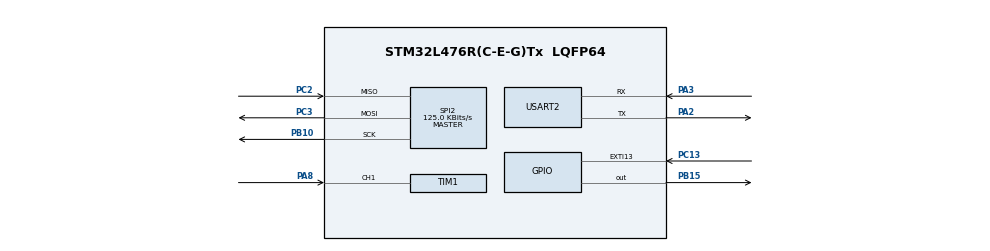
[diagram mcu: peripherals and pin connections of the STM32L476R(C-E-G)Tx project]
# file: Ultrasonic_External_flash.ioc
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Mcu.Family=STM32L4
Mcu.Name=STM32L476R(C-E-G)Tx
Mcu.Package=LQFP64
NVIC.EXTI15_10_IRQn=true\:0\:0\:false\:false\:true\:true\:true\:true
NVIC.PriorityGroup=NVIC_PRIORITYGROUP_4
NVIC.TIM1_CC_IRQn=true\:0\:0\:false\:false\:true\:true\:true\:true
PA2.Mode=Asynchronous
PA2.Signal=USART2_TX
PA3.Mode=Asynchronous
PA3.Signal=USART2_RX
PA8.Signal=S_TIM1_CH1
PB10.Mode=Full_Duplex_Master
PB10.Signal=SPI2_SCK
PB15.Signal=GPIO_Output
PC13.Signal=GPXTI13
PC2.Mode=Full_Duplex_Master
PC2.Signal=SPI2_MISO
PC3.Mode=Full_Duplex_Master
PC3.Signal=SPI2_MOSI
PH0-OSC_IN\ (PH0).Mode=HSE-External-Oscillator
PH0-OSC_IN\ (PH0).Signal=RCC_OSC_IN
PH1-OSC_OUT\ (PH1).Mode=HSE-External-Oscillator
PH1-OSC_OUT\ (PH1).Signal=RCC_OSC_OUT
ProjectManager.HeapSize=0x200
ProjectManager.StackSize=0x400
ProjectManager.TargetToolchain=STM32CubeIDE
RCC.HSE_VALUE=8000000
RCC.HSI_VALUE=16000000
RCC.LSE_VALUE=32768
RCC.MSI_VALUE=4000000
RCC.VCOOutputFreq_Value=32000000
SH.S_TIM1_CH1.0=TIM1_CH1,Input_Capture1_from_TI1
SPI2.BaudRatePrescaler=SPI_BAUDRATEPRESCALER_32
SPI2.CalculateBaudRate=125.0 KBits/s
SPI2.DataSize=SPI_DATASIZE_8BIT
SPI2.Direction=SPI_DIRECTION_2LINES
SPI2.Mode=SPI_MODE_MASTER
SPI2.VirtualType=VM_MASTER
TIM1.Channel-Input_Capture1_from_TI1=TIM_CHANNEL_1
TIM1.Prescaler=80-1
USART2.VirtualMode-Asynchronous=VM_ASYNC
board=custom

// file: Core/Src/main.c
/* USER CODE BEGIN Header */
/**
  ******************************************************************************
  * @file           : main.c
  * @brief          : Main program body
  ******************************************************************************
  * @attention
  *
  * Copyright (c) 2025 STMicroelectronics.
  * All rights reserved.
  *
  ******************************************************************************
  */
/* USER CODE END Header */
#include "main.h"

/* USER CODE BEGIN Includes */
#include "w25qxx.h"
#include <stdio.h>
#include <string.h>
/* USER CODE END Includes */

void SystemClock_Config(void);
static void MX_GPIO_Init(void);
static void MX_USART2_UART_Init(void);
static void MX_TIM1_Init(void);
static void MX_SPI2_Init(void);

SPI_HandleTypeDef hspi2;
TIM_HandleTypeDef htim1;
UART_HandleTypeDef huart2;

/* USER CODE BEGIN PV */
uint32_t IC_Val1 = 0;
uint32_t IC_Val2 = 0;
uint32_t Difference = 0;
uint8_t Is_First_Captured = 0;
uint16_t Distance = 0, object_present = 0;
uint8_t flash_buffer[256];
uint32_t ID;
/* USER CODE END PV */

/* USER CODE BEGIN PD */
#define TRIG_PIN   GPIO_PIN_15
#define TRIG_PORT  GPIOB
/* USER CODE END PD */

/* USER CODE BEGIN 0 */

void HAL_TIM_IC_CaptureCallback(TIM_HandleTypeDef *htim)
{
    if (htim->Channel == HAL_TIM_ACTIVE_CHANNEL_1)
    {
        if (Is_First_Captured == 0)
        {
            IC_Val1 = HAL_TIM_ReadCapturedValue(htim, TIM_CHANNEL_1);
            Is_First_Captured = 1;
            __HAL_TIM_SET_CAPTUREPOLARITY(htim, TIM_CHANNEL_1,
                                          TIM_INPUTCHANNELPOLARITY_FALLING);
        }
        else
        {
            IC_Val2 = HAL_TIM_ReadCapturedValue(htim, TIM_CHANNEL_1);
            __HAL_TIM_SET_COUNTER(htim, 0);

            if (IC_Val2 > IC_Val1)
                Difference = IC_Val2 - IC_Val1;
            else
                Difference = (0xffff - IC_Val1) + IC_Val2;

            Distance = (uint16_t)(Difference * 0.034f / 2.0f);

            Is_First_Captured = 0;
            __HAL_TIM_SET_CAPTUREPOLARITY(htim, TIM_CHANNEL_1,
                                          TIM_INPUTCHANNELPOLARITY_RISING);
            __HAL_TIM_DISABLE_IT(&htim1, TIM_IT_CC1);
        }
    }
}

uint16_t HCSR04_Read(void)
{
    uint32_t timeout = HAL_GetTick();

    HAL_GPIO_WritePin(TRIG_PORT, TRIG_PIN, GPIO_PIN_SET);
    for (volatile int i = 0; i < 800; i++);
    HAL_GPIO_WritePin(TRIG_PORT, TRIG_PIN, GPIO_PIN_RESET);

    __HAL_TIM_ENABLE_IT(&htim1, TIM_IT_CC1);

    while (Is_First_Captured || Distance == 0)
    {
        if ((HAL_GetTick() - timeout) > 30)
        {
            Distance = 0;
            break;
        }
    }
    return Distance;
}

/* Button EXTI callback: reads flash pages and prints via UART */
void HAL_GPIO_EXTI_Callback(uint16_t GPIO_Pin)
{
    if (GPIO_Pin == B1_Pin)
    {
        HAL_UART_Transmit(&huart2, (uint8_t *)"\r\n--- FLASH LOG DUMP ---\r\n", 27, 200);

        for (uint8_t i = 0; i < 10; i++)
        {
            memset(flash_buffer, 0, sizeof(flash_buffer));
            /* read page i, offset 0, up to 256 bytes */
            W25q_Read(i, 0, 256, flash_buffer);
            flash_buffer[255] = '\0';   // force null termination

            // find first 0xFF or 0x00 to stop
            for(int k = 0; k < 256; k++)
            {
                if(flash_buffer[k] == 0xFF || flash_buffer[k] == 0x00)
                {
                    flash_buffer[k] = '\0';
                    break;
                }
            }

            HAL_UART_Transmit(&huart2, flash_buffer, strlen((char*)flash_buffer), 200);

        }

        HAL_UART_Transmit(&huart2, (uint8_t *)"--- END ---\r\n", 13, 100);
    }
}

/* USER CODE END 0 */

int main(void)
{
  HAL_Init();
  SystemClock_Config();

  MX_GPIO_Init();
  MX_USART2_UART_Init();
  MX_TIM1_Init();
  MX_SPI2_Init();

  HAL_TIM_IC_Start_IT(&htim1, TIM_CHANNEL_1);

  /* Initialize / reset flash and read ID */
  W25Q_RESET();
  ID = W25_ReadID();

  uint8_t cnt = 0;
  uint16_t last_d = 0;

  while (1)
  {
      Distance = HCSR04_Read();

      if (Distance > 0 && Distance < 150)
      {
          if (object_present == 0)
          {
              char msg[80];
              int len = snprintf(msg, sizeof(msg), "Object entered: %u cm\r\n", Distance);
              if (len > 0)
              {
                  HAL_UART_Transmit(&huart2, (uint8_t *)msg, (uint16_t)len, 100);
                  flash_write(cnt, 0, (uint32_t)len, (uint8_t *)msg); // write then increment
                  cnt++;
              }

              last_d = Distance;
              object_present = 1;
          }
      }
      else
      {
          if (object_present == 1)
          {
              char msg[80];
              int len = snprintf(msg, sizeof(msg), "Object removed: %u cm\r\n", last_d);
              if (len > 0)
              {
                  HAL_UART_Transmit(&huart2, (uint8_t *)msg, (uint16_t)len, 100);
                  flash_write(cnt, 0, (uint32_t)len, (uint8_t *)msg); // write then increment
                  cnt++;
              }

              object_present = 0;
          }
      }

      if (cnt >= 10) cnt = 0; /* simple circular 10-page buffer */

      HAL_Delay(200);
  }
}

/* ---------------- System and Peripheral Initialization -------------------- */

void SystemClock_Config(void)
{
  RCC_OscInitTypeDef RCC_OscInitStruct = {0};
  RCC_ClkInitTypeDef RCC_ClkInitStruct = {0};

  if (HAL_PWREx_ControlVoltageScaling(PWR_REGULATOR_VOLTAGE_SCALE1) != HAL_OK)
  {
    Error_Handler();
  }

  RCC_OscInitStruct.OscillatorType = RCC_OSCILLATORTYPE_HSI;
  RCC_OscInitStruct.HSIState = RCC_HSI_ON;
  RCC_OscInitStruct.HSICalibrationValue = RCC_HSICALIBRATION_DEFAULT;
  RCC_OscInitStruct.PLL.PLLState = RCC_PLL_ON;
  RCC_OscInitStruct.PLL.PLLSource = RCC_PLLSOURCE_HSI;
  RCC_OscInitStruct.PLL.PLLM = 1;
  RCC_OscInitStruct.PLL.PLLN = 10;
  RCC_OscInitStruct.PLL.PLLP = RCC_PLLP_DIV7;
  RCC_OscInitStruct.PLL.PLLQ = RCC_PLLQ_DIV2;
  RCC_OscInitStruct.PLL.PLLR = RCC_PLLR_DIV2;

  if (HAL_RCC_OscConfig(&RCC_OscInitStruct) != HAL_OK) Error_Handler();

  RCC_ClkInitStruct.ClockType = RCC_CLOCKTYPE_HCLK|RCC_CLOCKTYPE_SYSCLK
                              |RCC_CLOCKTYPE_PCLK1|RCC_CLOCKTYPE_PCLK2;
  RCC_ClkInitStruct.SYSCLKSource = RCC_SYSCLKSOURCE_PLLCLK;
  RCC_ClkInitStruct.AHBCLKDivider = RCC_SYSCLK_DIV1;
  RCC_ClkInitStruct.APB1CLKDivider = RCC_HCLK_DIV1;
  RCC_ClkInitStruct.APB2CLKDivider = RCC_HCLK_DIV1;

  if (HAL_RCC_ClockConfig(&RCC_ClkInitStruct, FLASH_LATENCY_4) != HAL_OK) Error_Handler();
}

static void MX_SPI2_Init(void)
{
  /* SPI2 init - master mode */
  hspi2.Instance = SPI2;
  hspi2.Init.Mode = SPI_MODE_MASTER;
  hspi2.Init.Direction = SPI_DIRECTION_2LINES;
  hspi2.Init.DataSize = SPI_DATASIZE_8BIT;
  hspi2.Init.CLKPolarity = SPI_POLARITY_LOW;
  hspi2.Init.CLKPhase = SPI_PHASE_1EDGE;
  hspi2.Init.NSS = SPI_NSS_SOFT;
  hspi2.Init.BaudRatePrescaler = SPI_BAUDRATEPRESCALER_32;
  hspi2.Init.FirstBit = SPI_FIRSTBIT_MSB;
  hspi2.Init.TIMode = SPI_TIMODE_DISABLE;
  hspi2.Init.CRCCalculation = SPI_CRCCALCULATION_DISABLE;

  if (HAL_SPI_Init(&hspi2) != HAL_OK) Error_Handler();
}

static void MX_TIM1_Init(void)
{
  TIM_MasterConfigTypeDef sMasterConfig = {0};
  TIM_IC_InitTypeDef sConfigIC = {0};

  htim1.Instance = TIM1;
  htim1.Init.Prescaler = 80 - 1;
  htim1.Init.CounterMode = TIM_COUNTERMODE_UP;
  htim1.Init.Period = 65535 - 1;
  htim1.Init.ClockDivision = TIM_CLOCKDIVISION_DIV1;
  htim1.Init.RepetitionCounter = 0;

  if (HAL_TIM_IC_Init(&htim1) != HAL_OK) Error_Handler();

  sMasterConfig.MasterOutputTrigger = TIM_TRGO_RESET;
  sMasterConfig.MasterSlaveMode = TIM_MASTERSLAVEMODE_DISABLE;
  if (HAL_TIMEx_MasterConfigSynchronization(&htim1, &sMasterConfig) != HAL_OK) Error_Handler();

  sConfigIC.ICPolarity = TIM_INPUTCHANNELPOLARITY_RISING;
  sConfigIC.ICSelection = TIM_ICSELECTION_DIRECTTI;
  sConfigIC.ICPrescaler = TIM_ICPSC_DIV1;
  sConfigIC.ICFilter = 0;
  if (HAL_TIM_IC_ConfigChannel(&htim1, &sConfigIC, TIM_CHANNEL_1) != HAL_OK) Error_Handler();
}

static void MX_USART2_UART_Init(void)
{
  huart2.Instance = USART2;
  huart2.Init.BaudRate = 115200;
  huart2.Init.WordLength = UART_WORDLENGTH_8B;
  huart2.Init.StopBits = UART_STOPBITS_1;
  huart2.Init.Parity = UART_PARITY_NONE;
  huart2.Init.Mode = UART_MODE_TX_RX;
  huart2.Init.OverSampling = UART_OVERSAMPLING_16;
  huart2.Init.OneBitSampling = UART_ONE_BIT_SAMPLE_DISABLE;
  huart2.AdvancedInit.AdvFeatureInit = UART_ADVFEATURE_NO_INIT;
  if (HAL_UART_Init(&huart2) != HAL_OK) Error_Handler();
}

static void MX_GPIO_Init(void)
{
  GPIO_InitTypeDef GPIO_InitStruct = {0};

  /* GPIO Clocks */
  __HAL_RCC_GPIOC_CLK_ENABLE();
  __HAL_RCC_GPIOH_CLK_ENABLE();
  __HAL_RCC_GPIOA_CLK_ENABLE();
  __HAL_RCC_GPIOB_CLK_ENABLE();

  /* Configure Button B1 : PC13 (EXTI) */
  GPIO_InitStruct.Pin = B1_Pin;
  GPIO_InitStruct.Mode = GPIO_MODE_IT_FALLING;
  GPIO_InitStruct.Pull = GPIO_NOPULL;
  HAL_GPIO_Init(B1_GPIO_Port, &GPIO_InitStruct);

  /* Enable EXTI IRQ */
  HAL_NVIC_SetPriority(EXTI15_10_IRQn, 0, 0);
  HAL_NVIC_EnableIRQ(EXTI15_10_IRQn);

  /* Configure TRIG pin PB15 (output) */
  GPIO_InitStruct.Pin = TRIG_PIN;
  GPIO_InitStruct.Mode = GPIO_MODE_OUTPUT_PP;
  GPIO_InitStruct.Pull = GPIO_NOPULL;
  GPIO_InitStruct.Speed = GPIO_SPEED_FREQ_LOW;
  HAL_GPIO_Init(TRIG_PORT, &GPIO_InitStruct);

  /* Configure TIM1 CH1 input PA8 (AF) */
  GPIO_InitStruct.Pin = GPIO_PIN_8;
  GPIO_InitStruct.Mode = GPIO_MODE_AF_PP;
  GPIO_InitStruct.Pull = GPIO_NOPULL;
  GPIO_InitStruct.Speed = GPIO_SPEED_FREQ_LOW;
  GPIO_InitStruct.Alternate = GPIO_AF1_TIM1;
  HAL_GPIO_Init(GPIOA, &GPIO_InitStruct);

  /* ---------------- SPI2 pins ----------------
     SCK -> PB13 (AF)
     MISO -> PB14 (AF)
     MOSI -> PC3  (AF)  <--- important (you chose PC3)
     CS   -> PB12  (GPIO output) - manage manually in your SPI helper (csLOW()/csHIGH())
  -------------------------------------------------*/

  /* SPI2 SCK PB13, MISO PB14 */
  GPIO_InitStruct.Pin = GPIO_PIN_13 | GPIO_PIN_14;
  GPIO_InitStruct.Mode = GPIO_MODE_AF_PP;
  GPIO_InitStruct.Pull = GPIO_NOPULL;
  GPIO_InitStruct.Speed = GPIO_SPEED_FREQ_VERY_HIGH;
  GPIO_InitStruct.Alternate = GPIO_AF5_SPI2;
  HAL_GPIO_Init(GPIOB, &GPIO_InitStruct);

  /* SPI2 MOSI PC3 */
  GPIO_InitStruct.Pin = GPIO_PIN_3;
  GPIO_InitStruct.Mode = GPIO_MODE_AF_PP;
  GPIO_InitStruct.Pull = GPIO_NOPULL;
  GPIO_InitStruct.Speed = GPIO_SPEED_FREQ_VERY_HIGH;
  GPIO_InitStruct.Alternate = GPIO_AF5_SPI2;
  HAL_GPIO_Init(GPIOC, &GPIO_InitStruct);

  /* SPI2 CS PB12 as GPIO output */
  GPIO_InitStruct.Pin = GPIO_PIN_12;
  GPIO_InitStruct.Mode = GPIO_MODE_OUTPUT_PP;
  GPIO_InitStruct.Pull = GPIO_NOPULL;
  GPIO_InitStruct.Speed = GPIO_SPEED_FREQ_LOW;
  HAL_GPIO_Init(GPIOB, &GPIO_InitStruct);

  /* Optionally configure LED pin (LD2) if present */
#ifdef LD2_Pin
  GPIO_InitStruct.Pin = LD2_Pin;
  GPIO_InitStruct.Mode = GPIO_MODE_OUTPUT_PP;
  GPIO_InitStruct.Pull = GPIO_NOPULL;
  GPIO_InitStruct.Speed = GPIO_SPEED_FREQ_LOW;
  HAL_GPIO_Init(LD2_GPIO_Port, &GPIO_InitStruct);
#endif
}

void Error_Handler(void)
{
  __disable_irq();
  while (1) { }
}
